VERSION 5.7 ;
  NOWIREEXTENSIONATPIN ON ;
  DIVIDERCHAR "/" ;
  BUSBITCHARS "[]" ;
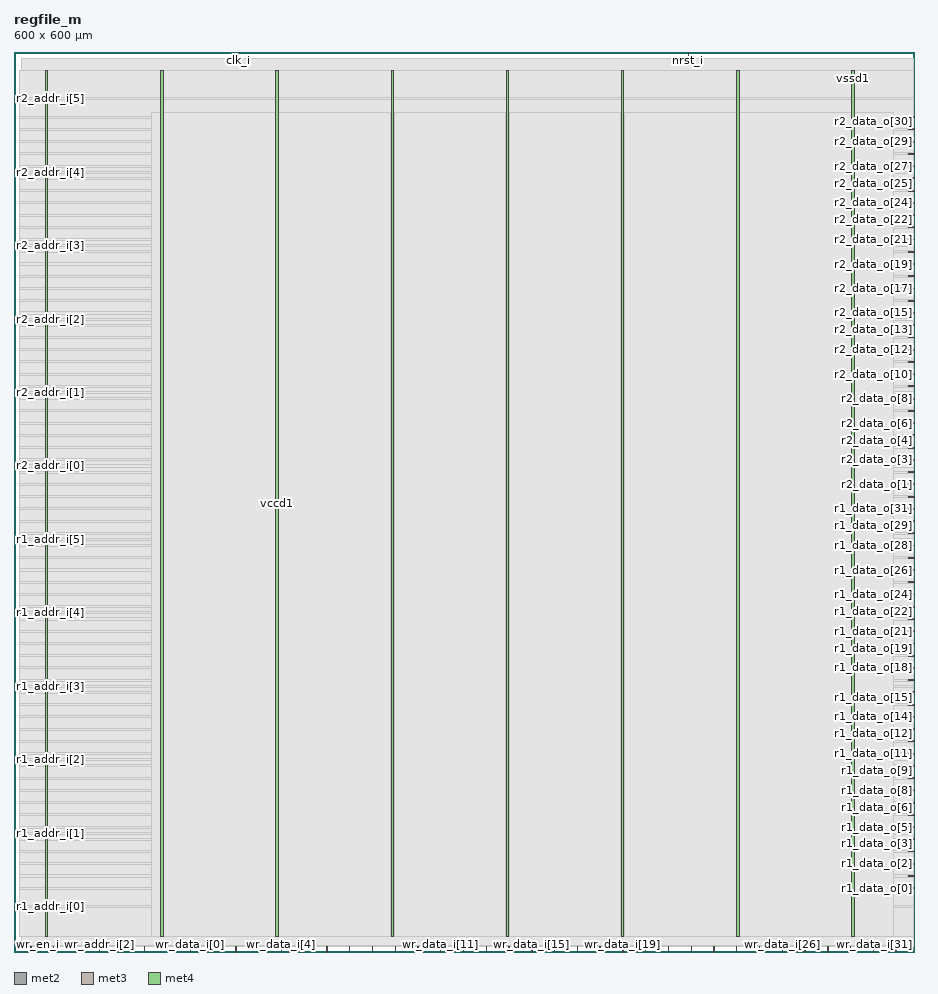
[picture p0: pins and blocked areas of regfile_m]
MACRO regfile_m
  CLASS BLOCK ;
  FOREIGN regfile_m ;
  ORIGIN 0.000 0.000 ;
  SIZE 600.000 BY 600.000 ;
  PIN clk_i
    DIRECTION INPUT ;
    USE SIGNAL ;
    ANTENNAGATEAREA 0.852000 ;
    ANTENNADIFFAREA 0.434700 ;
    PORT
      LAYER met2 ;
        RECT 149.590 596.000 149.870 600.000 ;
    END
  END clk_i
  PIN nrst_i
    DIRECTION INPUT ;
    USE SIGNAL ;
    ANTENNAGATEAREA 0.495000 ;
    PORT
      LAYER met2 ;
        RECT 449.510 596.000 449.790 600.000 ;
    END
  END nrst_i
  PIN r1_addr_i[0]
    DIRECTION INPUT ;
    USE SIGNAL ;
    ANTENNAGATEAREA 0.990000 ;
    PORT
      LAYER met3 ;
        RECT 0.000 29.960 4.000 30.560 ;
    END
  END r1_addr_i[0]
  PIN r1_addr_i[1]
    DIRECTION INPUT ;
    USE SIGNAL ;
    ANTENNAGATEAREA 0.990000 ;
    PORT
      LAYER met3 ;
        RECT 0.000 78.920 4.000 79.520 ;
    END
  END r1_addr_i[1]
  PIN r1_addr_i[2]
    DIRECTION INPUT ;
    USE SIGNAL ;
    ANTENNAGATEAREA 0.742500 ;
    PORT
      LAYER met3 ;
        RECT 0.000 127.880 4.000 128.480 ;
    END
  END r1_addr_i[2]
  PIN r1_addr_i[3]
    DIRECTION INPUT ;
    USE SIGNAL ;
    ANTENNAGATEAREA 0.742500 ;
    PORT
      LAYER met3 ;
        RECT 0.000 176.840 4.000 177.440 ;
    END
  END r1_addr_i[3]
  PIN r1_addr_i[4]
    DIRECTION INPUT ;
    USE SIGNAL ;
    ANTENNAGATEAREA 0.247500 ;
    PORT
      LAYER met3 ;
        RECT 0.000 225.800 4.000 226.400 ;
    END
  END r1_addr_i[4]
  PIN r1_addr_i[5]
    DIRECTION INPUT ;
    USE SIGNAL ;
    ANTENNAGATEAREA 0.213000 ;
    PORT
      LAYER met3 ;
        RECT 0.000 274.760 4.000 275.360 ;
    END
  END r1_addr_i[5]
  PIN r1_data_o[0]
    DIRECTION OUTPUT TRISTATE ;
    USE SIGNAL ;
    ANTENNADIFFAREA 2.673000 ;
    PORT
      LAYER met3 ;
        RECT 596.000 42.200 600.000 42.800 ;
    END
  END r1_data_o[0]
  PIN r1_data_o[10]
    DIRECTION OUTPUT TRISTATE ;
    USE SIGNAL ;
    ANTENNADIFFAREA 2.673000 ;
    PORT
      LAYER met3 ;
        RECT 596.000 123.800 600.000 124.400 ;
    END
  END r1_data_o[10]
  PIN r1_data_o[11]
    DIRECTION OUTPUT TRISTATE ;
    USE SIGNAL ;
    ANTENNADIFFAREA 2.673000 ;
    PORT
      LAYER met3 ;
        RECT 596.000 131.960 600.000 132.560 ;
    END
  END r1_data_o[11]
  PIN r1_data_o[12]
    DIRECTION OUTPUT TRISTATE ;
    USE SIGNAL ;
    ANTENNADIFFAREA 2.673000 ;
    PORT
      LAYER met3 ;
        RECT 596.000 140.120 600.000 140.720 ;
    END
  END r1_data_o[12]
  PIN r1_data_o[13]
    DIRECTION OUTPUT TRISTATE ;
    USE SIGNAL ;
    ANTENNADIFFAREA 2.673000 ;
    PORT
      LAYER met3 ;
        RECT 596.000 148.280 600.000 148.880 ;
    END
  END r1_data_o[13]
  PIN r1_data_o[14]
    DIRECTION OUTPUT TRISTATE ;
    USE SIGNAL ;
    ANTENNADIFFAREA 2.673000 ;
    PORT
      LAYER met3 ;
        RECT 596.000 156.440 600.000 157.040 ;
    END
  END r1_data_o[14]
  PIN r1_data_o[15]
    DIRECTION OUTPUT TRISTATE ;
    USE SIGNAL ;
    ANTENNADIFFAREA 2.673000 ;
    PORT
      LAYER met3 ;
        RECT 596.000 164.600 600.000 165.200 ;
    END
  END r1_data_o[15]
  PIN r1_data_o[16]
    DIRECTION OUTPUT TRISTATE ;
    USE SIGNAL ;
    ANTENNADIFFAREA 2.673000 ;
    PORT
      LAYER met3 ;
        RECT 596.000 172.760 600.000 173.360 ;
    END
  END r1_data_o[16]
  PIN r1_data_o[17]
    DIRECTION OUTPUT TRISTATE ;
    USE SIGNAL ;
    ANTENNADIFFAREA 2.673000 ;
    PORT
      LAYER met3 ;
        RECT 596.000 180.920 600.000 181.520 ;
    END
  END r1_data_o[17]
  PIN r1_data_o[18]
    DIRECTION OUTPUT TRISTATE ;
    USE SIGNAL ;
    ANTENNADIFFAREA 2.673000 ;
    PORT
      LAYER met3 ;
        RECT 596.000 189.080 600.000 189.680 ;
    END
  END r1_data_o[18]
  PIN r1_data_o[19]
    DIRECTION OUTPUT TRISTATE ;
    USE SIGNAL ;
    ANTENNADIFFAREA 2.673000 ;
    PORT
      LAYER met3 ;
        RECT 596.000 197.240 600.000 197.840 ;
    END
  END r1_data_o[19]
  PIN r1_data_o[1]
    DIRECTION OUTPUT TRISTATE ;
    USE SIGNAL ;
    ANTENNADIFFAREA 2.673000 ;
    PORT
      LAYER met3 ;
        RECT 596.000 50.360 600.000 50.960 ;
    END
  END r1_data_o[1]
  PIN r1_data_o[20]
    DIRECTION OUTPUT TRISTATE ;
    USE SIGNAL ;
    ANTENNADIFFAREA 2.673000 ;
    PORT
      LAYER met3 ;
        RECT 596.000 205.400 600.000 206.000 ;
    END
  END r1_data_o[20]
  PIN r1_data_o[21]
    DIRECTION OUTPUT TRISTATE ;
    USE SIGNAL ;
    ANTENNADIFFAREA 2.673000 ;
    PORT
      LAYER met3 ;
        RECT 596.000 213.560 600.000 214.160 ;
    END
  END r1_data_o[21]
  PIN r1_data_o[22]
    DIRECTION OUTPUT TRISTATE ;
    USE SIGNAL ;
    ANTENNADIFFAREA 2.673000 ;
    PORT
      LAYER met3 ;
        RECT 596.000 221.720 600.000 222.320 ;
    END
  END r1_data_o[22]
  PIN r1_data_o[23]
    DIRECTION OUTPUT TRISTATE ;
    USE SIGNAL ;
    ANTENNADIFFAREA 2.673000 ;
    PORT
      LAYER met3 ;
        RECT 596.000 229.880 600.000 230.480 ;
    END
  END r1_data_o[23]
  PIN r1_data_o[24]
    DIRECTION OUTPUT TRISTATE ;
    USE SIGNAL ;
    ANTENNADIFFAREA 2.673000 ;
    PORT
      LAYER met3 ;
        RECT 596.000 238.040 600.000 238.640 ;
    END
  END r1_data_o[24]
  PIN r1_data_o[25]
    DIRECTION OUTPUT TRISTATE ;
    USE SIGNAL ;
    ANTENNADIFFAREA 2.673000 ;
    PORT
      LAYER met3 ;
        RECT 596.000 246.200 600.000 246.800 ;
    END
  END r1_data_o[25]
  PIN r1_data_o[26]
    DIRECTION OUTPUT TRISTATE ;
    USE SIGNAL ;
    ANTENNADIFFAREA 2.673000 ;
    PORT
      LAYER met3 ;
        RECT 596.000 254.360 600.000 254.960 ;
    END
  END r1_data_o[26]
  PIN r1_data_o[27]
    DIRECTION OUTPUT TRISTATE ;
    USE SIGNAL ;
    ANTENNADIFFAREA 2.673000 ;
    PORT
      LAYER met3 ;
        RECT 596.000 262.520 600.000 263.120 ;
    END
  END r1_data_o[27]
  PIN r1_data_o[28]
    DIRECTION OUTPUT TRISTATE ;
    USE SIGNAL ;
    ANTENNADIFFAREA 2.673000 ;
    PORT
      LAYER met3 ;
        RECT 596.000 270.680 600.000 271.280 ;
    END
  END r1_data_o[28]
  PIN r1_data_o[29]
    DIRECTION OUTPUT TRISTATE ;
    USE SIGNAL ;
    ANTENNADIFFAREA 2.673000 ;
    PORT
      LAYER met3 ;
        RECT 596.000 278.840 600.000 279.440 ;
    END
  END r1_data_o[29]
  PIN r1_data_o[2]
    DIRECTION OUTPUT TRISTATE ;
    USE SIGNAL ;
    ANTENNADIFFAREA 2.673000 ;
    PORT
      LAYER met3 ;
        RECT 596.000 58.520 600.000 59.120 ;
    END
  END r1_data_o[2]
  PIN r1_data_o[30]
    DIRECTION OUTPUT TRISTATE ;
    USE SIGNAL ;
    ANTENNADIFFAREA 2.673000 ;
    PORT
      LAYER met3 ;
        RECT 596.000 287.000 600.000 287.600 ;
    END
  END r1_data_o[30]
  PIN r1_data_o[31]
    DIRECTION OUTPUT TRISTATE ;
    USE SIGNAL ;
    ANTENNADIFFAREA 2.673000 ;
    PORT
      LAYER met3 ;
        RECT 596.000 295.160 600.000 295.760 ;
    END
  END r1_data_o[31]
  PIN r1_data_o[3]
    DIRECTION OUTPUT TRISTATE ;
    USE SIGNAL ;
    ANTENNADIFFAREA 2.673000 ;
    PORT
      LAYER met3 ;
        RECT 596.000 66.680 600.000 67.280 ;
    END
  END r1_data_o[3]
  PIN r1_data_o[4]
    DIRECTION OUTPUT TRISTATE ;
    USE SIGNAL ;
    ANTENNADIFFAREA 2.673000 ;
    PORT
      LAYER met3 ;
        RECT 596.000 74.840 600.000 75.440 ;
    END
  END r1_data_o[4]
  PIN r1_data_o[5]
    DIRECTION OUTPUT TRISTATE ;
    USE SIGNAL ;
    ANTENNADIFFAREA 2.673000 ;
    PORT
      LAYER met3 ;
        RECT 596.000 83.000 600.000 83.600 ;
    END
  END r1_data_o[5]
  PIN r1_data_o[6]
    DIRECTION OUTPUT TRISTATE ;
    USE SIGNAL ;
    ANTENNADIFFAREA 2.673000 ;
    PORT
      LAYER met3 ;
        RECT 596.000 91.160 600.000 91.760 ;
    END
  END r1_data_o[6]
  PIN r1_data_o[7]
    DIRECTION OUTPUT TRISTATE ;
    USE SIGNAL ;
    ANTENNADIFFAREA 2.673000 ;
    PORT
      LAYER met3 ;
        RECT 596.000 99.320 600.000 99.920 ;
    END
  END r1_data_o[7]
  PIN r1_data_o[8]
    DIRECTION OUTPUT TRISTATE ;
    USE SIGNAL ;
    ANTENNADIFFAREA 2.673000 ;
    PORT
      LAYER met3 ;
        RECT 596.000 107.480 600.000 108.080 ;
    END
  END r1_data_o[8]
  PIN r1_data_o[9]
    DIRECTION OUTPUT TRISTATE ;
    USE SIGNAL ;
    ANTENNADIFFAREA 2.673000 ;
    PORT
      LAYER met3 ;
        RECT 596.000 115.640 600.000 116.240 ;
    END
  END r1_data_o[9]
  PIN r2_addr_i[0]
    DIRECTION INPUT ;
    USE SIGNAL ;
    ANTENNAGATEAREA 0.742500 ;
    PORT
      LAYER met3 ;
        RECT 0.000 323.720 4.000 324.320 ;
    END
  END r2_addr_i[0]
  PIN r2_addr_i[1]
    DIRECTION INPUT ;
    USE SIGNAL ;
    ANTENNAGATEAREA 0.742500 ;
    PORT
      LAYER met3 ;
        RECT 0.000 372.680 4.000 373.280 ;
    END
  END r2_addr_i[1]
  PIN r2_addr_i[2]
    DIRECTION INPUT ;
    USE SIGNAL ;
    ANTENNAGATEAREA 0.742500 ;
    PORT
      LAYER met3 ;
        RECT 0.000 421.640 4.000 422.240 ;
    END
  END r2_addr_i[2]
  PIN r2_addr_i[3]
    DIRECTION INPUT ;
    USE SIGNAL ;
    ANTENNAGATEAREA 0.742500 ;
    PORT
      LAYER met3 ;
        RECT 0.000 470.600 4.000 471.200 ;
    END
  END r2_addr_i[3]
  PIN r2_addr_i[4]
    DIRECTION INPUT ;
    USE SIGNAL ;
    ANTENNAGATEAREA 0.426000 ;
    PORT
      LAYER met3 ;
        RECT 0.000 519.560 4.000 520.160 ;
    END
  END r2_addr_i[4]
  PIN r2_addr_i[5]
    DIRECTION INPUT ;
    USE SIGNAL ;
    ANTENNAGATEAREA 0.426000 ;
    PORT
      LAYER met3 ;
        RECT 0.000 568.520 4.000 569.120 ;
    END
  END r2_addr_i[5]
  PIN r2_data_o[0]
    DIRECTION OUTPUT TRISTATE ;
    USE SIGNAL ;
    ANTENNADIFFAREA 2.673000 ;
    PORT
      LAYER met3 ;
        RECT 596.000 303.320 600.000 303.920 ;
    END
  END r2_data_o[0]
  PIN r2_data_o[10]
    DIRECTION OUTPUT TRISTATE ;
    USE SIGNAL ;
    ANTENNADIFFAREA 2.673000 ;
    PORT
      LAYER met3 ;
        RECT 596.000 384.920 600.000 385.520 ;
    END
  END r2_data_o[10]
  PIN r2_data_o[11]
    DIRECTION OUTPUT TRISTATE ;
    USE SIGNAL ;
    ANTENNADIFFAREA 2.673000 ;
    PORT
      LAYER met3 ;
        RECT 596.000 393.080 600.000 393.680 ;
    END
  END r2_data_o[11]
  PIN r2_data_o[12]
    DIRECTION OUTPUT TRISTATE ;
    USE SIGNAL ;
    ANTENNADIFFAREA 2.673000 ;
    PORT
      LAYER met3 ;
        RECT 596.000 401.240 600.000 401.840 ;
    END
  END r2_data_o[12]
  PIN r2_data_o[13]
    DIRECTION OUTPUT TRISTATE ;
    USE SIGNAL ;
    ANTENNADIFFAREA 2.673000 ;
    PORT
      LAYER met3 ;
        RECT 596.000 409.400 600.000 410.000 ;
    END
  END r2_data_o[13]
  PIN r2_data_o[14]
    DIRECTION OUTPUT TRISTATE ;
    USE SIGNAL ;
    ANTENNADIFFAREA 2.673000 ;
    PORT
      LAYER met3 ;
        RECT 596.000 417.560 600.000 418.160 ;
    END
  END r2_data_o[14]
  PIN r2_data_o[15]
    DIRECTION OUTPUT TRISTATE ;
    USE SIGNAL ;
    ANTENNADIFFAREA 2.673000 ;
    PORT
      LAYER met3 ;
        RECT 596.000 425.720 600.000 426.320 ;
    END
  END r2_data_o[15]
  PIN r2_data_o[16]
    DIRECTION OUTPUT TRISTATE ;
    USE SIGNAL ;
    ANTENNADIFFAREA 2.673000 ;
    PORT
      LAYER met3 ;
        RECT 596.000 433.880 600.000 434.480 ;
    END
  END r2_data_o[16]
  PIN r2_data_o[17]
    DIRECTION OUTPUT TRISTATE ;
    USE SIGNAL ;
    ANTENNADIFFAREA 2.673000 ;
    PORT
      LAYER met3 ;
        RECT 596.000 442.040 600.000 442.640 ;
    END
  END r2_data_o[17]
  PIN r2_data_o[18]
    DIRECTION OUTPUT TRISTATE ;
    USE SIGNAL ;
    ANTENNADIFFAREA 2.673000 ;
    PORT
      LAYER met3 ;
        RECT 596.000 450.200 600.000 450.800 ;
    END
  END r2_data_o[18]
  PIN r2_data_o[19]
    DIRECTION OUTPUT TRISTATE ;
    USE SIGNAL ;
    ANTENNADIFFAREA 2.673000 ;
    PORT
      LAYER met3 ;
        RECT 596.000 458.360 600.000 458.960 ;
    END
  END r2_data_o[19]
  PIN r2_data_o[1]
    DIRECTION OUTPUT TRISTATE ;
    USE SIGNAL ;
    ANTENNADIFFAREA 2.673000 ;
    PORT
      LAYER met3 ;
        RECT 596.000 311.480 600.000 312.080 ;
    END
  END r2_data_o[1]
  PIN r2_data_o[20]
    DIRECTION OUTPUT TRISTATE ;
    USE SIGNAL ;
    ANTENNADIFFAREA 2.673000 ;
    PORT
      LAYER met3 ;
        RECT 596.000 466.520 600.000 467.120 ;
    END
  END r2_data_o[20]
  PIN r2_data_o[21]
    DIRECTION OUTPUT TRISTATE ;
    USE SIGNAL ;
    ANTENNADIFFAREA 2.673000 ;
    PORT
      LAYER met3 ;
        RECT 596.000 474.680 600.000 475.280 ;
    END
  END r2_data_o[21]
  PIN r2_data_o[22]
    DIRECTION OUTPUT TRISTATE ;
    USE SIGNAL ;
    ANTENNADIFFAREA 2.673000 ;
    PORT
      LAYER met3 ;
        RECT 596.000 482.840 600.000 483.440 ;
    END
  END r2_data_o[22]
  PIN r2_data_o[23]
    DIRECTION OUTPUT TRISTATE ;
    USE SIGNAL ;
    ANTENNADIFFAREA 2.673000 ;
    PORT
      LAYER met3 ;
        RECT 596.000 491.000 600.000 491.600 ;
    END
  END r2_data_o[23]
  PIN r2_data_o[24]
    DIRECTION OUTPUT TRISTATE ;
    USE SIGNAL ;
    ANTENNADIFFAREA 2.673000 ;
    PORT
      LAYER met3 ;
        RECT 596.000 499.160 600.000 499.760 ;
    END
  END r2_data_o[24]
  PIN r2_data_o[25]
    DIRECTION OUTPUT TRISTATE ;
    USE SIGNAL ;
    ANTENNADIFFAREA 2.673000 ;
    PORT
      LAYER met3 ;
        RECT 596.000 507.320 600.000 507.920 ;
    END
  END r2_data_o[25]
  PIN r2_data_o[26]
    DIRECTION OUTPUT TRISTATE ;
    USE SIGNAL ;
    ANTENNADIFFAREA 2.673000 ;
    PORT
      LAYER met3 ;
        RECT 596.000 515.480 600.000 516.080 ;
    END
  END r2_data_o[26]
  PIN r2_data_o[27]
    DIRECTION OUTPUT TRISTATE ;
    USE SIGNAL ;
    ANTENNADIFFAREA 2.673000 ;
    PORT
      LAYER met3 ;
        RECT 596.000 523.640 600.000 524.240 ;
    END
  END r2_data_o[27]
  PIN r2_data_o[28]
    DIRECTION OUTPUT TRISTATE ;
    USE SIGNAL ;
    ANTENNADIFFAREA 2.673000 ;
    PORT
      LAYER met3 ;
        RECT 596.000 531.800 600.000 532.400 ;
    END
  END r2_data_o[28]
  PIN r2_data_o[29]
    DIRECTION OUTPUT TRISTATE ;
    USE SIGNAL ;
    ANTENNADIFFAREA 2.673000 ;
    PORT
      LAYER met3 ;
        RECT 596.000 539.960 600.000 540.560 ;
    END
  END r2_data_o[29]
  PIN r2_data_o[2]
    DIRECTION OUTPUT TRISTATE ;
    USE SIGNAL ;
    ANTENNADIFFAREA 2.673000 ;
    PORT
      LAYER met3 ;
        RECT 596.000 319.640 600.000 320.240 ;
    END
  END r2_data_o[2]
  PIN r2_data_o[30]
    DIRECTION OUTPUT TRISTATE ;
    USE SIGNAL ;
    ANTENNADIFFAREA 2.673000 ;
    PORT
      LAYER met3 ;
        RECT 596.000 548.120 600.000 548.720 ;
    END
  END r2_data_o[30]
  PIN r2_data_o[31]
    DIRECTION OUTPUT TRISTATE ;
    USE SIGNAL ;
    ANTENNADIFFAREA 2.673000 ;
    PORT
      LAYER met3 ;
        RECT 596.000 556.280 600.000 556.880 ;
    END
  END r2_data_o[31]
  PIN r2_data_o[3]
    DIRECTION OUTPUT TRISTATE ;
    USE SIGNAL ;
    ANTENNADIFFAREA 2.673000 ;
    PORT
      LAYER met3 ;
        RECT 596.000 327.800 600.000 328.400 ;
    END
  END r2_data_o[3]
  PIN r2_data_o[4]
    DIRECTION OUTPUT TRISTATE ;
    USE SIGNAL ;
    ANTENNADIFFAREA 2.673000 ;
    PORT
      LAYER met3 ;
        RECT 596.000 335.960 600.000 336.560 ;
    END
  END r2_data_o[4]
  PIN r2_data_o[5]
    DIRECTION OUTPUT TRISTATE ;
    USE SIGNAL ;
    ANTENNADIFFAREA 2.673000 ;
    PORT
      LAYER met3 ;
        RECT 596.000 344.120 600.000 344.720 ;
    END
  END r2_data_o[5]
  PIN r2_data_o[6]
    DIRECTION OUTPUT TRISTATE ;
    USE SIGNAL ;
    ANTENNADIFFAREA 2.673000 ;
    PORT
      LAYER met3 ;
        RECT 596.000 352.280 600.000 352.880 ;
    END
  END r2_data_o[6]
  PIN r2_data_o[7]
    DIRECTION OUTPUT TRISTATE ;
    USE SIGNAL ;
    ANTENNADIFFAREA 2.673000 ;
    PORT
      LAYER met3 ;
        RECT 596.000 360.440 600.000 361.040 ;
    END
  END r2_data_o[7]
  PIN r2_data_o[8]
    DIRECTION OUTPUT TRISTATE ;
    USE SIGNAL ;
    ANTENNADIFFAREA 2.673000 ;
    PORT
      LAYER met3 ;
        RECT 596.000 368.600 600.000 369.200 ;
    END
  END r2_data_o[8]
  PIN r2_data_o[9]
    DIRECTION OUTPUT TRISTATE ;
    USE SIGNAL ;
    ANTENNADIFFAREA 2.673000 ;
    PORT
      LAYER met3 ;
        RECT 596.000 376.760 600.000 377.360 ;
    END
  END r2_data_o[9]
  PIN vccd1
    DIRECTION INOUT ;
    USE POWER ;
    PORT
      LAYER met4 ;
        RECT 21.040 10.640 22.640 587.760 ;
    END
    PORT
      LAYER met4 ;
        RECT 174.640 10.640 176.240 587.760 ;
    END
    PORT
      LAYER met4 ;
        RECT 328.240 10.640 329.840 587.760 ;
    END
    PORT
      LAYER met4 ;
        RECT 481.840 10.640 483.440 587.760 ;
    END
  END vccd1
  PIN vssd1
    DIRECTION INOUT ;
    USE GROUND ;
    PORT
      LAYER met4 ;
        RECT 97.840 10.640 99.440 587.760 ;
    END
    PORT
      LAYER met4 ;
        RECT 251.440 10.640 253.040 587.760 ;
    END
    PORT
      LAYER met4 ;
        RECT 405.040 10.640 406.640 587.760 ;
    END
    PORT
      LAYER met4 ;
        RECT 558.640 10.640 560.240 587.760 ;
    END
  END vssd1
  PIN wr_addr_i[0]
    DIRECTION INPUT ;
    USE SIGNAL ;
    ANTENNAGATEAREA 0.495000 ;
    PORT
      LAYER met2 ;
        RECT 26.310 0.000 26.590 4.000 ;
    END
  END wr_addr_i[0]
  PIN wr_addr_i[1]
    DIRECTION INPUT ;
    USE SIGNAL ;
    ANTENNAGATEAREA 0.495000 ;
    PORT
      LAYER met2 ;
        RECT 41.490 0.000 41.770 4.000 ;
    END
  END wr_addr_i[1]
  PIN wr_addr_i[2]
    DIRECTION INPUT ;
    USE SIGNAL ;
    ANTENNAGATEAREA 0.495000 ;
    PORT
      LAYER met2 ;
        RECT 56.670 0.000 56.950 4.000 ;
    END
  END wr_addr_i[2]
  PIN wr_addr_i[3]
    DIRECTION INPUT ;
    USE SIGNAL ;
    ANTENNAGATEAREA 0.426000 ;
    PORT
      LAYER met2 ;
        RECT 71.850 0.000 72.130 4.000 ;
    END
  END wr_addr_i[3]
  PIN wr_addr_i[4]
    DIRECTION INPUT ;
    USE SIGNAL ;
    ANTENNAGATEAREA 0.213000 ;
    PORT
      LAYER met2 ;
        RECT 87.030 0.000 87.310 4.000 ;
    END
  END wr_addr_i[4]
  PIN wr_addr_i[5]
    DIRECTION INPUT ;
    USE SIGNAL ;
    ANTENNAGATEAREA 0.247500 ;
    PORT
      LAYER met2 ;
        RECT 102.210 0.000 102.490 4.000 ;
    END
  END wr_addr_i[5]
  PIN wr_data_i[0]
    DIRECTION INPUT ;
    USE SIGNAL ;
    ANTENNAGATEAREA 0.247500 ;
    PORT
      LAYER met2 ;
        RECT 117.390 0.000 117.670 4.000 ;
    END
  END wr_data_i[0]
  PIN wr_data_i[10]
    DIRECTION INPUT ;
    USE SIGNAL ;
    ANTENNAGATEAREA 0.213000 ;
    PORT
      LAYER met2 ;
        RECT 269.190 0.000 269.470 4.000 ;
    END
  END wr_data_i[10]
  PIN wr_data_i[11]
    DIRECTION INPUT ;
    USE SIGNAL ;
    ANTENNAGATEAREA 0.159000 ;
    PORT
      LAYER met2 ;
        RECT 284.370 0.000 284.650 4.000 ;
    END
  END wr_data_i[11]
  PIN wr_data_i[12]
    DIRECTION INPUT ;
    USE SIGNAL ;
    ANTENNAGATEAREA 0.213000 ;
    PORT
      LAYER met2 ;
        RECT 299.550 0.000 299.830 4.000 ;
    END
  END wr_data_i[12]
  PIN wr_data_i[13]
    DIRECTION INPUT ;
    USE SIGNAL ;
    ANTENNAGATEAREA 0.213000 ;
    PORT
      LAYER met2 ;
        RECT 314.730 0.000 315.010 4.000 ;
    END
  END wr_data_i[13]
  PIN wr_data_i[14]
    DIRECTION INPUT ;
    USE SIGNAL ;
    ANTENNAGATEAREA 0.159000 ;
    PORT
      LAYER met2 ;
        RECT 329.910 0.000 330.190 4.000 ;
    END
  END wr_data_i[14]
  PIN wr_data_i[15]
    DIRECTION INPUT ;
    USE SIGNAL ;
    ANTENNAGATEAREA 0.159000 ;
    PORT
      LAYER met2 ;
        RECT 345.090 0.000 345.370 4.000 ;
    END
  END wr_data_i[15]
  PIN wr_data_i[16]
    DIRECTION INPUT ;
    USE SIGNAL ;
    ANTENNAGATEAREA 0.247500 ;
    PORT
      LAYER met2 ;
        RECT 360.270 0.000 360.550 4.000 ;
    END
  END wr_data_i[16]
  PIN wr_data_i[17]
    DIRECTION INPUT ;
    USE SIGNAL ;
    ANTENNAGATEAREA 0.213000 ;
    PORT
      LAYER met2 ;
        RECT 375.450 0.000 375.730 4.000 ;
    END
  END wr_data_i[17]
  PIN wr_data_i[18]
    DIRECTION INPUT ;
    USE SIGNAL ;
    ANTENNAGATEAREA 0.213000 ;
    PORT
      LAYER met2 ;
        RECT 390.630 0.000 390.910 4.000 ;
    END
  END wr_data_i[18]
  PIN wr_data_i[19]
    DIRECTION INPUT ;
    USE SIGNAL ;
    ANTENNAGATEAREA 0.213000 ;
    PORT
      LAYER met2 ;
        RECT 405.810 0.000 406.090 4.000 ;
    END
  END wr_data_i[19]
  PIN wr_data_i[1]
    DIRECTION INPUT ;
    USE SIGNAL ;
    ANTENNAGATEAREA 0.213000 ;
    PORT
      LAYER met2 ;
        RECT 132.570 0.000 132.850 4.000 ;
    END
  END wr_data_i[1]
  PIN wr_data_i[20]
    DIRECTION INPUT ;
    USE SIGNAL ;
    ANTENNAGATEAREA 0.213000 ;
    PORT
      LAYER met2 ;
        RECT 420.990 0.000 421.270 4.000 ;
    END
  END wr_data_i[20]
  PIN wr_data_i[21]
    DIRECTION INPUT ;
    USE SIGNAL ;
    ANTENNAGATEAREA 0.213000 ;
    PORT
      LAYER met2 ;
        RECT 436.170 0.000 436.450 4.000 ;
    END
  END wr_data_i[21]
  PIN wr_data_i[22]
    DIRECTION INPUT ;
    USE SIGNAL ;
    ANTENNAGATEAREA 0.213000 ;
    PORT
      LAYER met2 ;
        RECT 451.350 0.000 451.630 4.000 ;
    END
  END wr_data_i[22]
  PIN wr_data_i[23]
    DIRECTION INPUT ;
    USE SIGNAL ;
    ANTENNAGATEAREA 0.213000 ;
    PORT
      LAYER met2 ;
        RECT 466.530 0.000 466.810 4.000 ;
    END
  END wr_data_i[23]
  PIN wr_data_i[24]
    DIRECTION INPUT ;
    USE SIGNAL ;
    ANTENNAGATEAREA 0.247500 ;
    PORT
      LAYER met2 ;
        RECT 481.710 0.000 481.990 4.000 ;
    END
  END wr_data_i[24]
  PIN wr_data_i[25]
    DIRECTION INPUT ;
    USE SIGNAL ;
    ANTENNAGATEAREA 0.247500 ;
    PORT
      LAYER met2 ;
        RECT 496.890 0.000 497.170 4.000 ;
    END
  END wr_data_i[25]
  PIN wr_data_i[26]
    DIRECTION INPUT ;
    USE SIGNAL ;
    ANTENNAGATEAREA 0.247500 ;
    PORT
      LAYER met2 ;
        RECT 512.070 0.000 512.350 4.000 ;
    END
  END wr_data_i[26]
  PIN wr_data_i[27]
    DIRECTION INPUT ;
    USE SIGNAL ;
    ANTENNAGATEAREA 0.247500 ;
    PORT
      LAYER met2 ;
        RECT 527.250 0.000 527.530 4.000 ;
    END
  END wr_data_i[27]
  PIN wr_data_i[28]
    DIRECTION INPUT ;
    USE SIGNAL ;
    ANTENNAGATEAREA 0.247500 ;
    PORT
      LAYER met2 ;
        RECT 542.430 0.000 542.710 4.000 ;
    END
  END wr_data_i[28]
  PIN wr_data_i[29]
    DIRECTION INPUT ;
    USE SIGNAL ;
    ANTENNAGATEAREA 0.247500 ;
    PORT
      LAYER met2 ;
        RECT 557.610 0.000 557.890 4.000 ;
    END
  END wr_data_i[29]
  PIN wr_data_i[2]
    DIRECTION INPUT ;
    USE SIGNAL ;
    ANTENNAGATEAREA 0.247500 ;
    PORT
      LAYER met2 ;
        RECT 147.750 0.000 148.030 4.000 ;
    END
  END wr_data_i[2]
  PIN wr_data_i[30]
    DIRECTION INPUT ;
    USE SIGNAL ;
    ANTENNAGATEAREA 0.247500 ;
    PORT
      LAYER met2 ;
        RECT 572.790 0.000 573.070 4.000 ;
    END
  END wr_data_i[30]
  PIN wr_data_i[31]
    DIRECTION INPUT ;
    USE SIGNAL ;
    ANTENNAGATEAREA 0.247500 ;
    PORT
      LAYER met2 ;
        RECT 587.970 0.000 588.250 4.000 ;
    END
  END wr_data_i[31]
  PIN wr_data_i[3]
    DIRECTION INPUT ;
    USE SIGNAL ;
    ANTENNAGATEAREA 0.213000 ;
    PORT
      LAYER met2 ;
        RECT 162.930 0.000 163.210 4.000 ;
    END
  END wr_data_i[3]
  PIN wr_data_i[4]
    DIRECTION INPUT ;
    USE SIGNAL ;
    ANTENNAGATEAREA 0.213000 ;
    PORT
      LAYER met2 ;
        RECT 178.110 0.000 178.390 4.000 ;
    END
  END wr_data_i[4]
  PIN wr_data_i[5]
    DIRECTION INPUT ;
    USE SIGNAL ;
    ANTENNAGATEAREA 0.213000 ;
    PORT
      LAYER met2 ;
        RECT 193.290 0.000 193.570 4.000 ;
    END
  END wr_data_i[5]
  PIN wr_data_i[6]
    DIRECTION INPUT ;
    USE SIGNAL ;
    ANTENNAGATEAREA 0.213000 ;
    PORT
      LAYER met2 ;
        RECT 208.470 0.000 208.750 4.000 ;
    END
  END wr_data_i[6]
  PIN wr_data_i[7]
    DIRECTION INPUT ;
    USE SIGNAL ;
    ANTENNAGATEAREA 0.213000 ;
    PORT
      LAYER met2 ;
        RECT 223.650 0.000 223.930 4.000 ;
    END
  END wr_data_i[7]
  PIN wr_data_i[8]
    DIRECTION INPUT ;
    USE SIGNAL ;
    ANTENNAGATEAREA 0.213000 ;
    PORT
      LAYER met2 ;
        RECT 238.830 0.000 239.110 4.000 ;
    END
  END wr_data_i[8]
  PIN wr_data_i[9]
    DIRECTION INPUT ;
    USE SIGNAL ;
    ANTENNAGATEAREA 0.213000 ;
    PORT
      LAYER met2 ;
        RECT 254.010 0.000 254.290 4.000 ;
    END
  END wr_data_i[9]
  PIN wr_en_i
    DIRECTION INPUT ;
    USE SIGNAL ;
    ANTENNAGATEAREA 0.247500 ;
    PORT
      LAYER met2 ;
        RECT 11.130 0.000 11.410 4.000 ;
    END
  END wr_en_i
  OBS
      LAYER li1 ;
        RECT 5.520 10.795 594.320 587.605 ;
      LAYER met1 ;
        RECT 4.670 10.240 599.770 587.760 ;
      LAYER met2 ;
        RECT 4.690 595.720 149.310 596.000 ;
        RECT 150.150 595.720 449.230 596.000 ;
        RECT 450.070 595.720 599.750 596.000 ;
        RECT 4.690 4.280 599.750 595.720 ;
        RECT 4.690 4.000 10.850 4.280 ;
        RECT 11.690 4.000 26.030 4.280 ;
        RECT 26.870 4.000 41.210 4.280 ;
        RECT 42.050 4.000 56.390 4.280 ;
        RECT 57.230 4.000 71.570 4.280 ;
        RECT 72.410 4.000 86.750 4.280 ;
        RECT 87.590 4.000 101.930 4.280 ;
        RECT 102.770 4.000 117.110 4.280 ;
        RECT 117.950 4.000 132.290 4.280 ;
        RECT 133.130 4.000 147.470 4.280 ;
        RECT 148.310 4.000 162.650 4.280 ;
        RECT 163.490 4.000 177.830 4.280 ;
        RECT 178.670 4.000 193.010 4.280 ;
        RECT 193.850 4.000 208.190 4.280 ;
        RECT 209.030 4.000 223.370 4.280 ;
        RECT 224.210 4.000 238.550 4.280 ;
        RECT 239.390 4.000 253.730 4.280 ;
        RECT 254.570 4.000 268.910 4.280 ;
        RECT 269.750 4.000 284.090 4.280 ;
        RECT 284.930 4.000 299.270 4.280 ;
        RECT 300.110 4.000 314.450 4.280 ;
        RECT 315.290 4.000 329.630 4.280 ;
        RECT 330.470 4.000 344.810 4.280 ;
        RECT 345.650 4.000 359.990 4.280 ;
        RECT 360.830 4.000 375.170 4.280 ;
        RECT 376.010 4.000 390.350 4.280 ;
        RECT 391.190 4.000 405.530 4.280 ;
        RECT 406.370 4.000 420.710 4.280 ;
        RECT 421.550 4.000 435.890 4.280 ;
        RECT 436.730 4.000 451.070 4.280 ;
        RECT 451.910 4.000 466.250 4.280 ;
        RECT 467.090 4.000 481.430 4.280 ;
        RECT 482.270 4.000 496.610 4.280 ;
        RECT 497.450 4.000 511.790 4.280 ;
        RECT 512.630 4.000 526.970 4.280 ;
        RECT 527.810 4.000 542.150 4.280 ;
        RECT 542.990 4.000 557.330 4.280 ;
        RECT 558.170 4.000 572.510 4.280 ;
        RECT 573.350 4.000 587.690 4.280 ;
        RECT 588.530 4.000 599.750 4.280 ;
      LAYER met3 ;
        RECT 3.990 569.520 599.775 587.685 ;
        RECT 4.400 568.120 599.775 569.520 ;
        RECT 3.990 557.280 599.775 568.120 ;
        RECT 3.990 555.880 595.600 557.280 ;
        RECT 3.990 549.120 599.775 555.880 ;
        RECT 3.990 547.720 595.600 549.120 ;
        RECT 3.990 540.960 599.775 547.720 ;
        RECT 3.990 539.560 595.600 540.960 ;
        RECT 3.990 532.800 599.775 539.560 ;
        RECT 3.990 531.400 595.600 532.800 ;
        RECT 3.990 524.640 599.775 531.400 ;
        RECT 3.990 523.240 595.600 524.640 ;
        RECT 3.990 520.560 599.775 523.240 ;
        RECT 4.400 519.160 599.775 520.560 ;
        RECT 3.990 516.480 599.775 519.160 ;
        RECT 3.990 515.080 595.600 516.480 ;
        RECT 3.990 508.320 599.775 515.080 ;
        RECT 3.990 506.920 595.600 508.320 ;
        RECT 3.990 500.160 599.775 506.920 ;
        RECT 3.990 498.760 595.600 500.160 ;
        RECT 3.990 492.000 599.775 498.760 ;
        RECT 3.990 490.600 595.600 492.000 ;
        RECT 3.990 483.840 599.775 490.600 ;
        RECT 3.990 482.440 595.600 483.840 ;
        RECT 3.990 475.680 599.775 482.440 ;
        RECT 3.990 474.280 595.600 475.680 ;
        RECT 3.990 471.600 599.775 474.280 ;
        RECT 4.400 470.200 599.775 471.600 ;
        RECT 3.990 467.520 599.775 470.200 ;
        RECT 3.990 466.120 595.600 467.520 ;
        RECT 3.990 459.360 599.775 466.120 ;
        RECT 3.990 457.960 595.600 459.360 ;
        RECT 3.990 451.200 599.775 457.960 ;
        RECT 3.990 449.800 595.600 451.200 ;
        RECT 3.990 443.040 599.775 449.800 ;
        RECT 3.990 441.640 595.600 443.040 ;
        RECT 3.990 434.880 599.775 441.640 ;
        RECT 3.990 433.480 595.600 434.880 ;
        RECT 3.990 426.720 599.775 433.480 ;
        RECT 3.990 425.320 595.600 426.720 ;
        RECT 3.990 422.640 599.775 425.320 ;
        RECT 4.400 421.240 599.775 422.640 ;
        RECT 3.990 418.560 599.775 421.240 ;
        RECT 3.990 417.160 595.600 418.560 ;
        RECT 3.990 410.400 599.775 417.160 ;
        RECT 3.990 409.000 595.600 410.400 ;
        RECT 3.990 402.240 599.775 409.000 ;
        RECT 3.990 400.840 595.600 402.240 ;
        RECT 3.990 394.080 599.775 400.840 ;
        RECT 3.990 392.680 595.600 394.080 ;
        RECT 3.990 385.920 599.775 392.680 ;
        RECT 3.990 384.520 595.600 385.920 ;
        RECT 3.990 377.760 599.775 384.520 ;
        RECT 3.990 376.360 595.600 377.760 ;
        RECT 3.990 373.680 599.775 376.360 ;
        RECT 4.400 372.280 599.775 373.680 ;
        RECT 3.990 369.600 599.775 372.280 ;
        RECT 3.990 368.200 595.600 369.600 ;
        RECT 3.990 361.440 599.775 368.200 ;
        RECT 3.990 360.040 595.600 361.440 ;
        RECT 3.990 353.280 599.775 360.040 ;
        RECT 3.990 351.880 595.600 353.280 ;
        RECT 3.990 345.120 599.775 351.880 ;
        RECT 3.990 343.720 595.600 345.120 ;
        RECT 3.990 336.960 599.775 343.720 ;
        RECT 3.990 335.560 595.600 336.960 ;
        RECT 3.990 328.800 599.775 335.560 ;
        RECT 3.990 327.400 595.600 328.800 ;
        RECT 3.990 324.720 599.775 327.400 ;
        RECT 4.400 323.320 599.775 324.720 ;
        RECT 3.990 320.640 599.775 323.320 ;
        RECT 3.990 319.240 595.600 320.640 ;
        RECT 3.990 312.480 599.775 319.240 ;
        RECT 3.990 311.080 595.600 312.480 ;
        RECT 3.990 304.320 599.775 311.080 ;
        RECT 3.990 302.920 595.600 304.320 ;
        RECT 3.990 296.160 599.775 302.920 ;
        RECT 3.990 294.760 595.600 296.160 ;
        RECT 3.990 288.000 599.775 294.760 ;
        RECT 3.990 286.600 595.600 288.000 ;
        RECT 3.990 279.840 599.775 286.600 ;
        RECT 3.990 278.440 595.600 279.840 ;
        RECT 3.990 275.760 599.775 278.440 ;
        RECT 4.400 274.360 599.775 275.760 ;
        RECT 3.990 271.680 599.775 274.360 ;
        RECT 3.990 270.280 595.600 271.680 ;
        RECT 3.990 263.520 599.775 270.280 ;
        RECT 3.990 262.120 595.600 263.520 ;
        RECT 3.990 255.360 599.775 262.120 ;
        RECT 3.990 253.960 595.600 255.360 ;
        RECT 3.990 247.200 599.775 253.960 ;
        RECT 3.990 245.800 595.600 247.200 ;
        RECT 3.990 239.040 599.775 245.800 ;
        RECT 3.990 237.640 595.600 239.040 ;
        RECT 3.990 230.880 599.775 237.640 ;
        RECT 3.990 229.480 595.600 230.880 ;
        RECT 3.990 226.800 599.775 229.480 ;
        RECT 4.400 225.400 599.775 226.800 ;
        RECT 3.990 222.720 599.775 225.400 ;
        RECT 3.990 221.320 595.600 222.720 ;
        RECT 3.990 214.560 599.775 221.320 ;
        RECT 3.990 213.160 595.600 214.560 ;
        RECT 3.990 206.400 599.775 213.160 ;
        RECT 3.990 205.000 595.600 206.400 ;
        RECT 3.990 198.240 599.775 205.000 ;
        RECT 3.990 196.840 595.600 198.240 ;
        RECT 3.990 190.080 599.775 196.840 ;
        RECT 3.990 188.680 595.600 190.080 ;
        RECT 3.990 181.920 599.775 188.680 ;
        RECT 3.990 180.520 595.600 181.920 ;
        RECT 3.990 177.840 599.775 180.520 ;
        RECT 4.400 176.440 599.775 177.840 ;
        RECT 3.990 173.760 599.775 176.440 ;
        RECT 3.990 172.360 595.600 173.760 ;
        RECT 3.990 165.600 599.775 172.360 ;
        RECT 3.990 164.200 595.600 165.600 ;
        RECT 3.990 157.440 599.775 164.200 ;
        RECT 3.990 156.040 595.600 157.440 ;
        RECT 3.990 149.280 599.775 156.040 ;
        RECT 3.990 147.880 595.600 149.280 ;
        RECT 3.990 141.120 599.775 147.880 ;
        RECT 3.990 139.720 595.600 141.120 ;
        RECT 3.990 132.960 599.775 139.720 ;
        RECT 3.990 131.560 595.600 132.960 ;
        RECT 3.990 128.880 599.775 131.560 ;
        RECT 4.400 127.480 599.775 128.880 ;
        RECT 3.990 124.800 599.775 127.480 ;
        RECT 3.990 123.400 595.600 124.800 ;
        RECT 3.990 116.640 599.775 123.400 ;
        RECT 3.990 115.240 595.600 116.640 ;
        RECT 3.990 108.480 599.775 115.240 ;
        RECT 3.990 107.080 595.600 108.480 ;
        RECT 3.990 100.320 599.775 107.080 ;
        RECT 3.990 98.920 595.600 100.320 ;
        RECT 3.990 92.160 599.775 98.920 ;
        RECT 3.990 90.760 595.600 92.160 ;
        RECT 3.990 84.000 599.775 90.760 ;
        RECT 3.990 82.600 595.600 84.000 ;
        RECT 3.990 79.920 599.775 82.600 ;
        RECT 4.400 78.520 599.775 79.920 ;
        RECT 3.990 75.840 599.775 78.520 ;
        RECT 3.990 74.440 595.600 75.840 ;
        RECT 3.990 67.680 599.775 74.440 ;
        RECT 3.990 66.280 595.600 67.680 ;
        RECT 3.990 59.520 599.775 66.280 ;
        RECT 3.990 58.120 595.600 59.520 ;
        RECT 3.990 51.360 599.775 58.120 ;
        RECT 3.990 49.960 595.600 51.360 ;
        RECT 3.990 43.200 599.775 49.960 ;
        RECT 3.990 41.800 595.600 43.200 ;
        RECT 3.990 30.960 599.775 41.800 ;
        RECT 4.400 29.560 599.775 30.960 ;
        RECT 3.990 10.375 599.775 29.560 ;
      LAYER met4 ;
        RECT 91.375 10.375 97.440 559.465 ;
        RECT 99.840 10.375 174.240 559.465 ;
        RECT 176.640 10.375 251.040 559.465 ;
        RECT 253.440 10.375 327.840 559.465 ;
        RECT 330.240 10.375 404.640 559.465 ;
        RECT 407.040 10.375 481.440 559.465 ;
        RECT 483.840 10.375 558.240 559.465 ;
        RECT 560.640 10.375 586.665 559.465 ;
  END
END regfile_m
END LIBRARY

